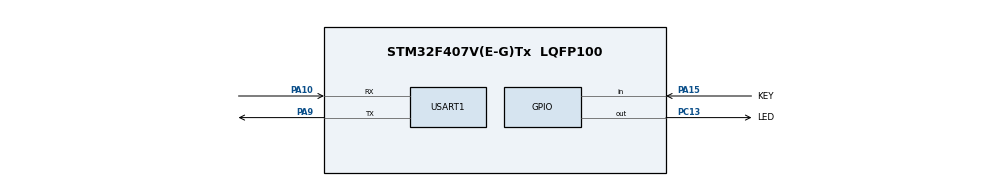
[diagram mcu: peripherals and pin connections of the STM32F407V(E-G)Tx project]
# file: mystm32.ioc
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Mcu.Family=STM32F4
Mcu.Name=STM32F407V(E-G)Tx
Mcu.Package=LQFP100
NVIC.PriorityGroup=NVIC_PRIORITYGROUP_4
NVIC.TIM1_UP_TIM10_IRQn=true\:15\:0\:false\:false\:true\:false\:true\:true
NVIC.TimeBase=TIM1_UP_TIM10_IRQn
NVIC.TimeBaseIP=TIM1
NVIC.USART1_IRQn=true\:4\:0\:true\:false\:true\:true\:true\:true
PA10.Mode=Asynchronous
PA10.Signal=USART1_RX
PA13.Mode=Serial_Wire
PA13.Signal=SYS_JTMS-SWDIO
PA14.Mode=Serial_Wire
PA14.Signal=SYS_JTCK-SWCLK
PA15.GPIO_Label=KEY
PA15.GPIO_PuPd=GPIO_PULLUP
PA15.Signal=GPIO_Input
PA9.Mode=Asynchronous
PA9.Signal=USART1_TX
PC13-ANTI_TAMP.GPIO_Label=LED
PC13-ANTI_TAMP.GPIO_Speed=GPIO_SPEED_FREQ_LOW
PC13-ANTI_TAMP.PinState=GPIO_PIN_SET
PC13-ANTI_TAMP.Signal=GPIO_Output
PC14-OSC32_IN.Mode=LSE-External-Oscillator
PC14-OSC32_IN.Signal=RCC_OSC32_IN
PC15-OSC32_OUT.Mode=LSE-External-Oscillator
PC15-OSC32_OUT.Signal=RCC_OSC32_OUT
PH0-OSC_IN.Mode=HSE-External-Oscillator
PH0-OSC_IN.Signal=RCC_OSC_IN
PH1-OSC_OUT.Mode=HSE-External-Oscillator
PH1-OSC_OUT.Signal=RCC_OSC_OUT
ProjectManager.HeapSize=0x200
ProjectManager.StackSize=0x400
ProjectManager.TargetToolchain=SW4STM32
RCC.48MHZClocksFreq_Value=84000000
RCC.AHBFreq_Value=168000000
RCC.APB1CLKDivider=RCC_HCLK_DIV4
RCC.APB1Freq_Value=42000000
RCC.APB1TimFreq_Value=84000000
RCC.APB2CLKDivider=RCC_HCLK_DIV2
RCC.APB2Freq_Value=84000000
RCC.APB2TimFreq_Value=168000000
RCC.CortexFreq_Value=168000000
RCC.EnbaleCSS=true
RCC.HCLKFreq_Value=168000000
RCC.HSE_VALUE=8000000
RCC.HSI_VALUE=16000000
RCC.PLLM=4
RCC.PLLN=168
RCC.PLLSourceVirtual=RCC_PLLSOURCE_HSE
RCC.SYSCLKFreq_VALUE=168000000
RCC.SYSCLKSource=RCC_SYSCLKSOURCE_PLLCLK
RCC.VCOOutputFreq_Value=336000000
USART1.VirtualMode=VM_ASYNC
VP_SYS_VS_tim1.Mode=TIM1
board=custom

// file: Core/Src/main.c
/* USER CODE BEGIN Header */
/**
  ******************************************************************************
  * @file           : main.c
  * @brief          : Main program body
  ******************************************************************************
  * @attention
  *
  * Copyright (c) 2022 STMicroelectronics.
  * All rights reserved.
  *
  * This software is licensed under terms that can be found in the LICENSE file
  * in the root directory of this software component.
  * If no LICENSE file comes with this software, it is provided AS-IS.
  *
  ******************************************************************************
  */
/* USER CODE END Header */
#include "main.h"
#include "gpio.h"

void SystemClock_Config(void);

int main(void)
{

  /* MCU Configuration--------------------------------------------------------*/

  /* Reset of all peripherals, Initializes the Flash interface and the Systick. */
  HAL_Init();

  /* Configure the system clock */
  SystemClock_Config();

  /* Initialize all configured peripherals */
  MX_GPIO_Init();
  MX_USART1_UART_Init();
  /* USER CODE BEGIN 2 */
	RetargetInit(&huart1);  // printf重定向到usart1
  printf("欢迎使用野火步进电机 加减速正反转 例程\r\n");
  // 步进电机初始化
  stepper_Init();
  // 打印帮助命令
  ShowHelp();
  /* USER CODE END 2 */

  /* Infinite loop */
  /* USER CODE BEGIN WHILE */
  while (1)
  {
    HAL_Delay(500);
    HAL_GPIO_WritePin(LED_GPIO_Port, LED_Pin, GPIO_PIN_RESET);
    HAL_Delay(500);
    HAL_GPIO_WritePin(LED_GPIO_Port, LED_Pin, GPIO_PIN_SET);
    // 处理串口数据
    DealSerialData();
    /* USER CODE END WHILE */

  }
}

void SystemClock_Config(void)
{
  RCC_OscInitTypeDef RCC_OscInitStruct = {0};
  RCC_ClkInitTypeDef RCC_ClkInitStruct = {0};

  /** Configure the main internal regulator output voltage
  */
  __HAL_RCC_PWR_CLK_ENABLE();
  __HAL_PWR_VOLTAGESCALING_CONFIG(PWR_REGULATOR_VOLTAGE_SCALE1);

  // 先将时钟源选择为内部时钟
  RCC_ClkInitStruct.ClockType = RCC_CLOCKTYPE_SYSCLK;
  RCC_ClkInitStruct.SYSCLKSource = RCC_SYSCLKSOURCE_HSI;
  if (HAL_RCC_ClockConfig(&RCC_ClkInitStruct, FLASH_LATENCY_5) != HAL_OK)
  {
    Error_Handler();
  }
  // 解决pll初始化设置问题 原文链接：https://blog.csdn.net/qq153471503/article/details/114700884

  /** Initializes the RCC Oscillators according to the specified parameters
  * in the RCC_OscInitTypeDef structure.
  */
  RCC_OscInitStruct.OscillatorType = RCC_OSCILLATORTYPE_HSE;
  RCC_OscInitStruct.HSEState = RCC_HSE_ON;
  RCC_OscInitStruct.PLL.PLLState = RCC_PLL_ON;
  RCC_OscInitStruct.PLL.PLLSource = RCC_PLLSOURCE_HSE;
  RCC_OscInitStruct.PLL.PLLM = 4;
  RCC_OscInitStruct.PLL.PLLN = 168;
  RCC_OscInitStruct.PLL.PLLP = RCC_PLLP_DIV2;
  RCC_OscInitStruct.PLL.PLLQ = 4;
  if (HAL_RCC_OscConfig(&RCC_OscInitStruct) != HAL_OK)
  {
    Error_Handler();
  }

  /** Initializes the CPU, AHB and APB buses clocks
  */
  RCC_ClkInitStruct.ClockType = RCC_CLOCKTYPE_HCLK|RCC_CLOCKTYPE_SYSCLK
                              |RCC_CLOCKTYPE_PCLK1|RCC_CLOCKTYPE_PCLK2;
  RCC_ClkInitStruct.SYSCLKSource = RCC_SYSCLKSOURCE_PLLCLK;
  RCC_ClkInitStruct.AHBCLKDivider = RCC_SYSCLK_DIV1;
  RCC_ClkInitStruct.APB1CLKDivider = RCC_HCLK_DIV4;
  RCC_ClkInitStruct.APB2CLKDivider = RCC_HCLK_DIV2;

  if (HAL_RCC_ClockConfig(&RCC_ClkInitStruct, FLASH_LATENCY_5) != HAL_OK)
  {
    Error_Handler();
  }

  // 禁用内部高速时钟
  RCC_OscInitStruct.OscillatorType = RCC_OSCILLATORTYPE_HSI;
  RCC_OscInitStruct.HSIState = RCC_HSI_OFF;
  RCC_OscInitStruct.PLL.PLLState = RCC_PLL_NONE;
  if(HAL_RCC_OscConfig(&RCC_OscInitStruct) != HAL_OK)
  {
    Error_Handler();
  }

  /** Enables the Clock Security System
  */
  HAL_RCC_EnableCSS();
}

void HAL_TIM_PeriodElapsedCallback(TIM_HandleTypeDef *htim)
{
  if (htim->Instance == TIM1) {
    HAL_IncTick();
  }
}

void Error_Handler(void)
{
  __disable_irq();
  while (1)
  {
  }
}
